# Copyright 2020 The SkyWater PDK Authors
#
# Licensed under the Apache License, Version 2.0 (the "License");
# you may not use this file except in compliance with the License.
# You may obtain a copy of the License at
#
#     https://www.apache.org/licenses/LICENSE-2.0
#
# Unless required by applicable law or agreed to in writing, software
# distributed under the License is distributed on an "AS IS" BASIS,
# WITHOUT WARRANTIES OR CONDITIONS OF ANY KIND, either express or implied.
# See the License for the specific language governing permissions and
# limitations under the License.
#
# SPDX-License-Identifier: Apache-2.0

VERSION 5.7 ;

BUSBITCHARS "[]" ;
DIVIDERCHAR "/" ;

UNITS
  TIME NANOSECONDS 1 ;
  CAPACITANCE PICOFARADS 1 ;
  RESISTANCE OHMS 1 ;
  DATABASE MICRONS 1000 ;
END UNITS

MANUFACTURINGGRID 0.005 ;

PROPERTYDEFINITIONS
  LAYER LEF58_TYPE STRING ;
END PROPERTYDEFINITIONS

SITE CoreSite
  CLASS CORE ;
  SYMMETRY Y ;
  SIZE 24 BY 24 ;
END CoreSite

SITE PadSite
  CLASS PAD ;
  SYMMETRY Y ;
  SIZE 1 BY 1 ;
END PadSite

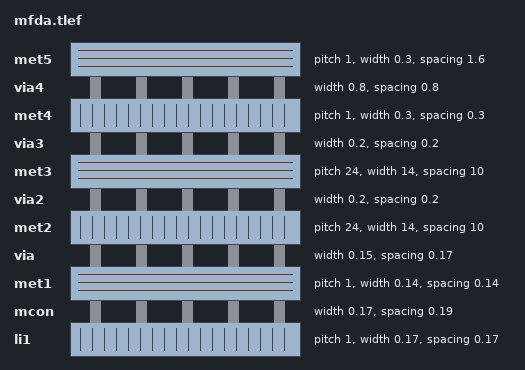
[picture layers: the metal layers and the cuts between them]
LAYER li1
  TYPE ROUTING ;
  DIRECTION VERTICAL ;
  PITCH 1 ;
  MINWIDTH 0.17 ;
  WIDTH 0.17 ;          # LI 1
  SPACING 0.17 ;     # LI 2
END li1

LAYER mcon
  TYPE CUT ;

  WIDTH 0.17 ;                # Mcon 1
  SPACING 0.19 ;              # Mcon 2
  ENCLOSURE BELOW 0 0 ;       # Mcon 4
  ENCLOSURE ABOVE 0.03 0.06 ; # Met1 4 / Met1 5

  ANTENNADIFFAREARATIO PWL ( ( 0 3 ) ( 0.0125 3 ) ( 0.0225 3.405 ) ( 22.5 408 ) ) ;
  DCCURRENTDENSITY AVERAGE 0.36 ; # mA per via Iavg_max at Tj = 90oC

END mcon

LAYER met1
  TYPE ROUTING ;
  DIRECTION HORIZONTAL ;
  PITCH 1 ;
  MINWIDTH 0.14 ;
  WIDTH 0.14 ;                     # Met1 1
  SPACING 0.14 ;                 # Met1 2
END met1

LAYER via
  TYPE CUT ;
  WIDTH 0.15 ;                  # Via 1a
  SPACING 0.17 ;                # Via 2
  ENCLOSURE BELOW 0.055 0.085 ; # Via 4a / Via 5a
  ENCLOSURE ABOVE 0.055 0.085 ; # Met2 4 / Met2 5

  ANTENNADIFFAREARATIO PWL ( ( 0 6 ) ( 0.0125 6 ) ( 0.0225 6.81 ) ( 22.5 816 ) ) ;
  DCCURRENTDENSITY AVERAGE 0.29 ; # mA per via Iavg_max at Tj = 90oC
END via

LAYER met2
  TYPE ROUTING ;
  DIRECTION VERTICAL ;
  PITCH 24 ;
  MINWIDTH 12 ;
  WIDTH 14 ;                        # Met2 1
  SPACING 10 ;                   # Met2 2
END met2

# ******** Layer via2, type routing, number 44 **************
LAYER via2
  TYPE CUT ;
  WIDTH 0.2 ;                   # Via2 1
  SPACING 0.2 ;                 # Via2 2
END via2

LAYER met3
  TYPE ROUTING ;
  DIRECTION HORIZONTAL ;
  PITCH 24 ;
  MINWIDTH 12 ;
  WIDTH 14 ;              # Met3 1
  SPACING 10 ;          # Met3 2
END met3

LAYER via3
  TYPE CUT ;
  WIDTH 0.2 ;                   # Via3 1
  SPACING 0.2 ;                 # Via3 2
  ENCLOSURE BELOW 0.06 0.09 ;   # Via3 4 / Via3 5
  ENCLOSURE ABOVE 0.065 0.065 ; # Met4 3
  ANTENNADIFFAREARATIO PWL ( ( 0 6 ) ( 0.0125 6 ) ( 0.0225 6.81 ) ( 22.5 816 ) ) ;
  DCCURRENTDENSITY AVERAGE 0.48 ; # mA per via Iavg_max at Tj = 90oC
END via3

LAYER met4
  TYPE ROUTING ;
  DIRECTION VERTICAL ;
  PITCH 1 ;
  MINWIDTH 0.3 ;
  WIDTH 0.3 ;             # Met4 1
  SPACING 0.3 ;             # Met4 2
END met4

LAYER via4
  TYPE CUT ;

  WIDTH 0.8 ;                 # Via4 1
  SPACING 0.8 ;               # Via4 2
  ENCLOSURE BELOW 0.19 0.19 ; # Via4 4
  ENCLOSURE ABOVE 0.31 0.31 ; # Met5 3
  ANTENNADIFFAREARATIO PWL ( ( 0 6 ) ( 0.0125 6 ) ( 0.0225 6.81 ) ( 22.5 816 ) ) ;
  DCCURRENTDENSITY AVERAGE 2.49 ; # mA per via Iavg_max at Tj = 90oC
END via4

LAYER met5
  TYPE ROUTING ;
  DIRECTION HORIZONTAL ;
  PITCH 1 ;
  MINWIDTH 0.3 ;
  WIDTH 0.3 ;            # Met5 1
  SPACING 1.6 ;        # Met5 2
END met5


### Routing via cells section   ###
VIA M2M3_PR_C DEFAULT
  LAYER via2 ;
  RECT -0.1 -0.1 0.1 0.1 ;
  LAYER met2 ;
  RECT -7 -7 7 7 ;
  LAYER met3 ;
  RECT -7 -7 7 7 ;
END M2M3_PR_C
